VERSION 5.7 ;
  NOWIREEXTENSIONATPIN ON ;
  DIVIDERCHAR "/" ;
  BUSBITCHARS "[]" ;
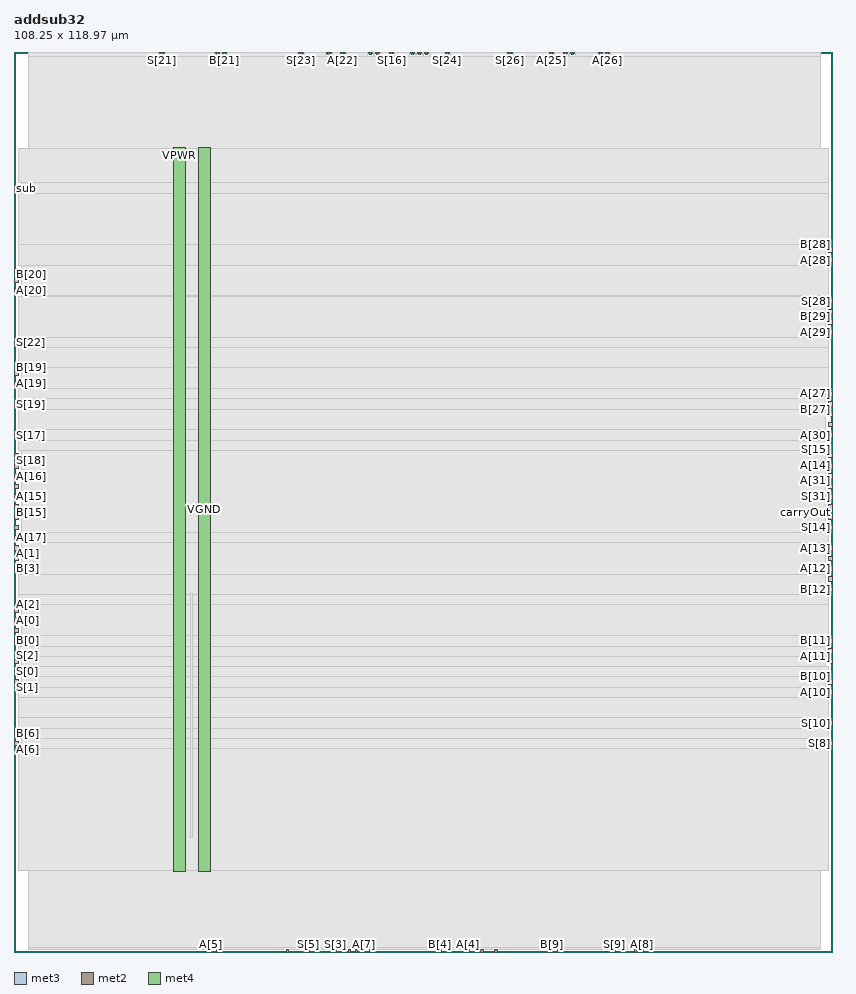
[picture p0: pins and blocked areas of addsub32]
MACRO addsub32
  CLASS BLOCK ;
  FOREIGN addsub32 ;
  ORIGIN 0.000 0.000 ;
  SIZE 108.250 BY 118.970 ;
  PIN A[0]
    DIRECTION INPUT ;
    USE SIGNAL ;
    ANTENNAGATEAREA 0.213000 ;
    PORT
      LAYER met3 ;
        RECT 0.000 43.560 0.600 44.160 ;
    END
  END A[0]
  PIN A[10]
    DIRECTION INPUT ;
    USE SIGNAL ;
    ANTENNAGATEAREA 0.213000 ;
    PORT
      LAYER met3 ;
        RECT 107.650 34.040 108.250 34.640 ;
    END
  END A[10]
  PIN A[11]
    DIRECTION INPUT ;
    USE SIGNAL ;
    ANTENNAGATEAREA 0.213000 ;
    PORT
      LAYER met3 ;
        RECT 107.650 39.480 108.250 40.080 ;
    END
  END A[11]
  PIN A[12]
    DIRECTION INPUT ;
    USE SIGNAL ;
    ANTENNAGATEAREA 0.213000 ;
    PORT
      LAYER met3 ;
        RECT 107.650 50.360 108.250 50.960 ;
    END
  END A[12]
  PIN A[13]
    DIRECTION INPUT ;
    USE SIGNAL ;
    ANTENNAGATEAREA 0.213000 ;
    PORT
      LAYER met3 ;
        RECT 107.650 53.080 108.250 53.680 ;
    END
  END A[13]
  PIN A[14]
    DIRECTION INPUT ;
    USE SIGNAL ;
    ANTENNAGATEAREA 0.213000 ;
    PORT
      LAYER met3 ;
        RECT 107.650 63.960 108.250 64.560 ;
    END
  END A[14]
  PIN A[15]
    DIRECTION INPUT ;
    USE SIGNAL ;
    ANTENNAGATEAREA 0.213000 ;
    PORT
      LAYER met3 ;
        RECT 0.000 59.880 0.600 60.480 ;
    END
  END A[15]
  PIN A[16]
    DIRECTION INPUT ;
    USE SIGNAL ;
    ANTENNAGATEAREA 0.213000 ;
    PORT
      LAYER met3 ;
        RECT 0.000 62.600 0.600 63.200 ;
    END
  END A[16]
  PIN A[17]
    DIRECTION INPUT ;
    USE SIGNAL ;
    ANTENNAGATEAREA 0.213000 ;
    PORT
      LAYER met3 ;
        RECT 0.000 54.440 0.600 55.040 ;
    END
  END A[17]
  PIN A[18]
    DIRECTION INPUT ;
    USE SIGNAL ;
    ANTENNAGATEAREA 0.213000 ;
    PORT
      LAYER met3 ;
        RECT 0.000 65.320 0.600 65.920 ;
    END
  END A[18]
  PIN A[19]
    DIRECTION INPUT ;
    USE SIGNAL ;
    ANTENNAGATEAREA 0.213000 ;
    PORT
      LAYER met3 ;
        RECT 0.000 74.840 0.600 75.440 ;
    END
  END A[19]
  PIN A[1]
    DIRECTION INPUT ;
    USE SIGNAL ;
    ANTENNAGATEAREA 0.213000 ;
    PORT
      LAYER met3 ;
        RECT 0.000 53.080 0.600 53.680 ;
    END
  END A[1]
  PIN A[20]
    DIRECTION INPUT ;
    USE SIGNAL ;
    ANTENNAGATEAREA 0.213000 ;
    PORT
      LAYER met3 ;
        RECT 0.000 87.080 0.600 87.680 ;
    END
  END A[20]
  PIN A[21]
    DIRECTION INPUT ;
    USE SIGNAL ;
    ANTENNAGATEAREA 0.213000 ;
    PORT
      LAYER met2 ;
        RECT 26.770 118.690 27.050 118.970 ;
    END
  END A[21]
  PIN A[22]
    DIRECTION INPUT ;
    USE SIGNAL ;
    ANTENNAGATEAREA 0.213000 ;
    PORT
      LAYER met2 ;
        RECT 43.330 118.690 43.610 118.970 ;
    END
  END A[22]
  PIN A[23]
    DIRECTION INPUT ;
    USE SIGNAL ;
    ANTENNAGATEAREA 0.213000 ;
    PORT
      LAYER met2 ;
        RECT 47.010 118.690 47.290 118.970 ;
    END
  END A[23]
  PIN A[24]
    DIRECTION INPUT ;
    USE SIGNAL ;
    ANTENNAGATEAREA 0.213000 ;
    PORT
      LAYER met2 ;
        RECT 52.530 118.690 52.810 118.970 ;
    END
  END A[24]
  PIN A[25]
    DIRECTION INPUT ;
    USE SIGNAL ;
    ANTENNAGATEAREA 0.213000 ;
    PORT
      LAYER met2 ;
        RECT 70.930 118.690 71.210 118.970 ;
    END
  END A[25]
  PIN A[26]
    DIRECTION INPUT ;
    USE SIGNAL ;
    ANTENNAGATEAREA 0.213000 ;
    PORT
      LAYER met2 ;
        RECT 78.290 118.690 78.570 118.970 ;
    END
  END A[26]
  PIN A[27]
    DIRECTION INPUT ;
    USE SIGNAL ;
    ANTENNAGATEAREA 0.213000 ;
    PORT
      LAYER met3 ;
        RECT 107.650 73.480 108.250 74.080 ;
    END
  END A[27]
  PIN A[28]
    DIRECTION INPUT ;
    USE SIGNAL ;
    ANTENNAGATEAREA 0.213000 ;
    PORT
      LAYER met3 ;
        RECT 107.650 91.160 108.250 91.760 ;
    END
  END A[28]
  PIN A[29]
    DIRECTION INPUT ;
    USE SIGNAL ;
    ANTENNAGATEAREA 0.213000 ;
    PORT
      LAYER met3 ;
        RECT 107.650 81.640 108.250 82.240 ;
    END
  END A[29]
  PIN A[2]
    DIRECTION INPUT ;
    USE SIGNAL ;
    ANTENNAGATEAREA 0.213000 ;
    PORT
      LAYER met3 ;
        RECT 0.000 44.920 0.600 45.520 ;
    END
  END A[2]
  PIN A[30]
    DIRECTION INPUT ;
    USE SIGNAL ;
    ANTENNAGATEAREA 0.213000 ;
    PORT
      LAYER met3 ;
        RECT 107.650 68.040 108.250 68.640 ;
    END
  END A[30]
  PIN A[31]
    DIRECTION INPUT ;
    USE SIGNAL ;
    ANTENNAGATEAREA 0.213000 ;
    PORT
      LAYER met3 ;
        RECT 107.650 61.240 108.250 61.840 ;
    END
  END A[31]
  PIN A[3]
    DIRECTION INPUT ;
    USE SIGNAL ;
    ANTENNAGATEAREA 0.213000 ;
    PORT
      LAYER met2 ;
        RECT 44.250 0.000 44.530 0.280 ;
    END
  END A[3]
  PIN A[4]
    DIRECTION INPUT ;
    USE SIGNAL ;
    ANTENNAGATEAREA 0.213000 ;
    PORT
      LAYER met2 ;
        RECT 59.890 0.000 60.170 0.280 ;
    END
  END A[4]
  PIN A[5]
    DIRECTION INPUT ;
    USE SIGNAL ;
    ANTENNAGATEAREA 0.213000 ;
    PORT
      LAYER met2 ;
        RECT 25.850 0.000 26.130 0.280 ;
    END
  END A[5]
  PIN A[6]
    DIRECTION INPUT ;
    USE SIGNAL ;
    ANTENNAGATEAREA 0.213000 ;
    PORT
      LAYER met3 ;
        RECT 0.000 27.240 0.600 27.840 ;
    END
  END A[6]
  PIN A[7]
    DIRECTION INPUT ;
    USE SIGNAL ;
    ANTENNAGATEAREA 0.213000 ;
    PORT
      LAYER met2 ;
        RECT 46.090 0.000 46.370 0.280 ;
    END
  END A[7]
  PIN A[8]
    DIRECTION INPUT ;
    USE SIGNAL ;
    ANTENNAGATEAREA 0.213000 ;
    PORT
      LAYER met2 ;
        RECT 82.890 0.000 83.170 0.280 ;
    END
  END A[8]
  PIN A[9]
    DIRECTION INPUT ;
    USE SIGNAL ;
    ANTENNAGATEAREA 0.213000 ;
    PORT
      LAYER met2 ;
        RECT 71.850 0.000 72.130 0.280 ;
    END
  END A[9]
  PIN B[0]
    DIRECTION INPUT ;
    USE SIGNAL ;
    ANTENNAGATEAREA 0.126000 ;
    PORT
      LAYER met3 ;
        RECT 0.000 40.840 0.600 41.440 ;
    END
  END B[0]
  PIN B[10]
    DIRECTION INPUT ;
    USE SIGNAL ;
    ANTENNAGATEAREA 0.213000 ;
    PORT
      LAYER met3 ;
        RECT 107.650 35.400 108.250 36.000 ;
    END
  END B[10]
  PIN B[11]
    DIRECTION INPUT ;
    USE SIGNAL ;
    ANTENNAGATEAREA 0.213000 ;
    PORT
      LAYER met3 ;
        RECT 107.650 40.840 108.250 41.440 ;
    END
  END B[11]
  PIN B[12]
    DIRECTION INPUT ;
    USE SIGNAL ;
    ANTENNAGATEAREA 0.213000 ;
    PORT
      LAYER met3 ;
        RECT 107.650 47.640 108.250 48.240 ;
    END
  END B[12]
  PIN B[13]
    DIRECTION INPUT ;
    USE SIGNAL ;
    ANTENNAGATEAREA 0.213000 ;
    PORT
      LAYER met3 ;
        RECT 107.650 51.720 108.250 52.320 ;
    END
  END B[13]
  PIN B[14]
    DIRECTION INPUT ;
    USE SIGNAL ;
    ANTENNAGATEAREA 0.213000 ;
    PORT
      LAYER met3 ;
        RECT 107.650 62.600 108.250 63.200 ;
    END
  END B[14]
  PIN B[15]
    DIRECTION INPUT ;
    USE SIGNAL ;
    ANTENNAGATEAREA 0.213000 ;
    PORT
      LAYER met3 ;
        RECT 0.000 58.520 0.600 59.120 ;
    END
  END B[15]
  PIN B[16]
    DIRECTION INPUT ;
    USE SIGNAL ;
    ANTENNAGATEAREA 0.213000 ;
    PORT
      LAYER met3 ;
        RECT 0.000 57.160 0.600 57.760 ;
    END
  END B[16]
  PIN B[17]
    DIRECTION INPUT ;
    USE SIGNAL ;
    ANTENNAGATEAREA 0.213000 ;
    PORT
      LAYER met3 ;
        RECT 0.000 55.800 0.600 56.400 ;
    END
  END B[17]
  PIN B[18]
    DIRECTION INPUT ;
    USE SIGNAL ;
    ANTENNAGATEAREA 0.213000 ;
    PORT
      LAYER met3 ;
        RECT 0.000 61.240 0.600 61.840 ;
    END
  END B[18]
  PIN B[19]
    DIRECTION INPUT ;
    USE SIGNAL ;
    ANTENNAGATEAREA 0.213000 ;
    PORT
      LAYER met3 ;
        RECT 0.000 76.200 0.600 76.800 ;
    END
  END B[19]
  PIN B[1]
    DIRECTION INPUT ;
    USE SIGNAL ;
    ANTENNAGATEAREA 0.213000 ;
    PORT
      LAYER met3 ;
        RECT 0.000 51.720 0.600 52.320 ;
    END
  END B[1]
  PIN B[20]
    DIRECTION INPUT ;
    USE SIGNAL ;
    ANTENNAGATEAREA 0.213000 ;
    PORT
      LAYER met3 ;
        RECT 0.000 88.440 0.600 89.040 ;
    END
  END B[20]
  PIN B[21]
    DIRECTION INPUT ;
    USE SIGNAL ;
    ANTENNAGATEAREA 0.213000 ;
    PORT
      LAYER met2 ;
        RECT 27.690 118.690 27.970 118.970 ;
    END
  END B[21]
  PIN B[22]
    DIRECTION INPUT ;
    USE SIGNAL ;
    ANTENNAGATEAREA 0.213000 ;
    PORT
      LAYER met2 ;
        RECT 41.490 118.690 41.770 118.970 ;
    END
  END B[22]
  PIN B[23]
    DIRECTION INPUT ;
    USE SIGNAL ;
    ANTENNAGATEAREA 0.213000 ;
    PORT
      LAYER met2 ;
        RECT 47.930 118.690 48.210 118.970 ;
    END
  END B[23]
  PIN B[24]
    DIRECTION INPUT ;
    USE SIGNAL ;
    ANTENNAGATEAREA 0.213000 ;
    PORT
      LAYER met2 ;
        RECT 54.370 118.690 54.650 118.970 ;
    END
  END B[24]
  PIN B[25]
    DIRECTION INPUT ;
    USE SIGNAL ;
    ANTENNAGATEAREA 0.213000 ;
    PORT
      LAYER met2 ;
        RECT 73.690 118.690 73.970 118.970 ;
    END
  END B[25]
  PIN B[26]
    DIRECTION INPUT ;
    USE SIGNAL ;
    ANTENNAGATEAREA 0.213000 ;
    PORT
      LAYER met2 ;
        RECT 77.370 118.690 77.650 118.970 ;
    END
  END B[26]
  PIN B[27]
    DIRECTION INPUT ;
    USE SIGNAL ;
    ANTENNAGATEAREA 0.213000 ;
    PORT
      LAYER met3 ;
        RECT 107.650 72.120 108.250 72.720 ;
    END
  END B[27]
  PIN B[28]
    DIRECTION INPUT ;
    USE SIGNAL ;
    ANTENNAGATEAREA 0.213000 ;
    PORT
      LAYER met3 ;
        RECT 107.650 92.520 108.250 93.120 ;
    END
  END B[28]
  PIN B[29]
    DIRECTION INPUT ;
    USE SIGNAL ;
    ANTENNAGATEAREA 0.213000 ;
    PORT
      LAYER met3 ;
        RECT 107.650 83.000 108.250 83.600 ;
    END
  END B[29]
  PIN B[2]
    DIRECTION INPUT ;
    USE SIGNAL ;
    ANTENNAGATEAREA 0.213000 ;
    PORT
      LAYER met3 ;
        RECT 0.000 42.200 0.600 42.800 ;
    END
  END B[2]
  PIN B[30]
    DIRECTION INPUT ;
    USE SIGNAL ;
    ANTENNAGATEAREA 0.213000 ;
    PORT
      LAYER met3 ;
        RECT 107.650 69.400 108.250 70.000 ;
    END
  END B[30]
  PIN B[31]
    DIRECTION INPUT ;
    USE SIGNAL ;
    ANTENNAGATEAREA 0.213000 ;
    PORT
      LAYER met3 ;
        RECT 107.650 57.160 108.250 57.760 ;
    END
  END B[31]
  PIN B[3]
    DIRECTION INPUT ;
    USE SIGNAL ;
    ANTENNAGATEAREA 0.213000 ;
    PORT
      LAYER met3 ;
        RECT 0.000 50.360 0.600 50.960 ;
    END
  END B[3]
  PIN B[4]
    DIRECTION INPUT ;
    USE SIGNAL ;
    ANTENNAGATEAREA 0.213000 ;
    PORT
      LAYER met2 ;
        RECT 56.210 0.000 56.490 0.280 ;
    END
  END B[4]
  PIN B[5]
    DIRECTION INPUT ;
    USE SIGNAL ;
    ANTENNAGATEAREA 0.213000 ;
    PORT
      LAYER met2 ;
        RECT 26.770 0.000 27.050 0.280 ;
    END
  END B[5]
  PIN B[6]
    DIRECTION INPUT ;
    USE SIGNAL ;
    ANTENNAGATEAREA 0.213000 ;
    PORT
      LAYER met3 ;
        RECT 0.000 28.600 0.600 29.200 ;
    END
  END B[6]
  PIN B[7]
    DIRECTION INPUT ;
    USE SIGNAL ;
    ANTENNAGATEAREA 0.213000 ;
    PORT
      LAYER met2 ;
        RECT 47.010 0.000 47.290 0.280 ;
    END
  END B[7]
  PIN B[8]
    DIRECTION INPUT ;
    USE SIGNAL ;
    ANTENNAGATEAREA 0.213000 ;
    PORT
      LAYER met2 ;
        RECT 81.970 0.000 82.250 0.280 ;
    END
  END B[8]
  PIN B[9]
    DIRECTION INPUT ;
    USE SIGNAL ;
    ANTENNAGATEAREA 0.213000 ;
    PORT
      LAYER met2 ;
        RECT 70.930 0.000 71.210 0.280 ;
    END
  END B[9]
  PIN S[0]
    DIRECTION OUTPUT ;
    USE SIGNAL ;
    ANTENNADIFFAREA 0.702900 ;
    PORT
      LAYER met3 ;
        RECT 0.000 36.760 0.600 37.360 ;
    END
  END S[0]
  PIN S[10]
    DIRECTION OUTPUT ;
    USE SIGNAL ;
    ANTENNADIFFAREA 0.383400 ;
    PORT
      LAYER met3 ;
        RECT 107.650 29.960 108.250 30.560 ;
    END
  END S[10]
  PIN S[11]
    DIRECTION OUTPUT ;
    USE SIGNAL ;
    ANTENNADIFFAREA 0.891000 ;
    PORT
      LAYER met3 ;
        RECT 107.650 38.120 108.250 38.720 ;
    END
  END S[11]
  PIN S[12]
    DIRECTION OUTPUT ;
    USE SIGNAL ;
    ANTENNAGATEAREA 0.126000 ;
    ANTENNADIFFAREA 0.429000 ;
    PORT
      LAYER met2 ;
        RECT 63.570 0.000 63.850 0.280 ;
    END
  END S[12]
  PIN S[13]
    DIRECTION OUTPUT ;
    USE SIGNAL ;
    ANTENNADIFFAREA 0.429000 ;
    PORT
      LAYER met3 ;
        RECT 107.650 49.000 108.250 49.600 ;
    END
  END S[13]
  PIN S[14]
    DIRECTION OUTPUT ;
    USE SIGNAL ;
    ANTENNADIFFAREA 1.336500 ;
    PORT
      LAYER met3 ;
        RECT 107.650 55.800 108.250 56.400 ;
    END
  END S[14]
  PIN S[15]
    DIRECTION OUTPUT ;
    USE SIGNAL ;
    ANTENNADIFFAREA 0.795200 ;
    PORT
      LAYER met3 ;
        RECT 107.650 65.320 108.250 65.920 ;
    END
  END S[15]
  PIN S[16]
    DIRECTION OUTPUT ;
    USE SIGNAL ;
    ANTENNADIFFAREA 1.336500 ;
    PORT
      LAYER met2 ;
        RECT 49.770 118.690 50.050 118.970 ;
    END
  END S[16]
  PIN S[17]
    DIRECTION OUTPUT ;
    USE SIGNAL ;
    ANTENNADIFFAREA 1.336500 ;
    PORT
      LAYER met3 ;
        RECT 0.000 68.040 0.600 68.640 ;
    END
  END S[17]
  PIN S[18]
    DIRECTION OUTPUT ;
    USE SIGNAL ;
    ANTENNADIFFAREA 1.336500 ;
    PORT
      LAYER met3 ;
        RECT 0.000 63.960 0.600 64.560 ;
    END
  END S[18]
  PIN S[19]
    DIRECTION OUTPUT ;
    USE SIGNAL ;
    ANTENNADIFFAREA 1.336500 ;
    PORT
      LAYER met3 ;
        RECT 0.000 72.120 0.600 72.720 ;
    END
  END S[19]
  PIN S[1]
    DIRECTION OUTPUT ;
    USE SIGNAL ;
    ANTENNADIFFAREA 1.336500 ;
    PORT
      LAYER met3 ;
        RECT 0.000 35.400 0.600 36.000 ;
    END
  END S[1]
  PIN S[20]
    DIRECTION OUTPUT ;
    USE SIGNAL ;
    ANTENNADIFFAREA 1.782000 ;
    PORT
      LAYER met3 ;
        RECT 0.000 89.800 0.600 90.400 ;
    END
  END S[20]
  PIN S[21]
    DIRECTION OUTPUT ;
    USE SIGNAL ;
    ANTENNADIFFAREA 1.782000 ;
    PORT
      LAYER met2 ;
        RECT 19.410 118.690 19.690 118.970 ;
    END
  END S[21]
  PIN S[22]
    DIRECTION OUTPUT ;
    USE SIGNAL ;
    ANTENNADIFFAREA 1.336500 ;
    PORT
      LAYER met3 ;
        RECT 0.000 80.280 0.600 80.880 ;
    END
  END S[22]
  PIN S[23]
    DIRECTION OUTPUT ;
    USE SIGNAL ;
    ANTENNADIFFAREA 1.336500 ;
    PORT
      LAYER met2 ;
        RECT 37.810 118.690 38.090 118.970 ;
    END
  END S[23]
  PIN S[24]
    DIRECTION OUTPUT ;
    USE SIGNAL ;
    ANTENNADIFFAREA 1.336500 ;
    PORT
      LAYER met2 ;
        RECT 57.130 118.690 57.410 118.970 ;
    END
  END S[24]
  PIN S[25]
    DIRECTION OUTPUT ;
    USE SIGNAL ;
    ANTENNADIFFAREA 1.336500 ;
    PORT
      LAYER met2 ;
        RECT 53.450 118.690 53.730 118.970 ;
    END
  END S[25]
  PIN S[26]
    DIRECTION OUTPUT ;
    USE SIGNAL ;
    ANTENNADIFFAREA 1.336500 ;
    PORT
      LAYER met2 ;
        RECT 65.410 118.690 65.690 118.970 ;
    END
  END S[26]
  PIN S[27]
    DIRECTION OUTPUT ;
    USE SIGNAL ;
    ANTENNADIFFAREA 1.336500 ;
    PORT
      LAYER met2 ;
        RECT 72.770 118.690 73.050 118.970 ;
    END
  END S[27]
  PIN S[28]
    DIRECTION OUTPUT ;
    USE SIGNAL ;
    ANTENNADIFFAREA 0.383400 ;
    PORT
      LAYER met3 ;
        RECT 107.650 85.720 108.250 86.320 ;
    END
  END S[28]
  PIN S[29]
    DIRECTION OUTPUT ;
    USE SIGNAL ;
    ANTENNADIFFAREA 0.795200 ;
    PORT
      LAYER met3 ;
        RECT 107.650 84.360 108.250 84.960 ;
    END
  END S[29]
  PIN S[2]
    DIRECTION OUTPUT ;
    USE SIGNAL ;
    ANTENNADIFFAREA 1.336500 ;
    PORT
      LAYER met3 ;
        RECT 0.000 38.120 0.600 38.720 ;
    END
  END S[2]
  PIN S[30]
    DIRECTION OUTPUT ;
    USE SIGNAL ;
    ANTENNADIFFAREA 1.336500 ;
    PORT
      LAYER met3 ;
        RECT 107.650 70.760 108.250 71.360 ;
    END
  END S[30]
  PIN S[31]
    DIRECTION OUTPUT ;
    USE SIGNAL ;
    ANTENNADIFFAREA 1.336500 ;
    PORT
      LAYER met3 ;
        RECT 107.650 59.880 108.250 60.480 ;
    END
  END S[31]
  PIN S[3]
    DIRECTION OUTPUT ;
    USE SIGNAL ;
    ANTENNADIFFAREA 1.336500 ;
    PORT
      LAYER met2 ;
        RECT 42.410 0.000 42.690 0.280 ;
    END
  END S[3]
  PIN S[4]
    DIRECTION OUTPUT ;
    USE SIGNAL ;
    ANTENNADIFFAREA 1.336500 ;
    PORT
      LAYER met2 ;
        RECT 61.730 0.000 62.010 0.280 ;
    END
  END S[4]
  PIN S[5]
    DIRECTION OUTPUT ;
    USE SIGNAL ;
    ANTENNADIFFAREA 1.336500 ;
    PORT
      LAYER met2 ;
        RECT 38.730 0.000 39.010 0.280 ;
    END
  END S[5]
  PIN S[6]
    DIRECTION OUTPUT ;
    USE SIGNAL ;
    ANTENNADIFFAREA 1.336500 ;
    PORT
      LAYER met2 ;
        RECT 35.970 0.000 36.250 0.280 ;
    END
  END S[6]
  PIN S[7]
    DIRECTION OUTPUT ;
    USE SIGNAL ;
    ANTENNADIFFAREA 1.336500 ;
    PORT
      LAYER met2 ;
        RECT 45.170 0.000 45.450 0.280 ;
    END
  END S[7]
  PIN S[8]
    DIRECTION OUTPUT ;
    USE SIGNAL ;
    ANTENNADIFFAREA 1.336500 ;
    PORT
      LAYER met3 ;
        RECT 107.650 27.240 108.250 27.840 ;
    END
  END S[8]
  PIN S[9]
    DIRECTION OUTPUT ;
    USE SIGNAL ;
    ANTENNADIFFAREA 0.891000 ;
    PORT
      LAYER met2 ;
        RECT 79.210 0.000 79.490 0.280 ;
    END
  END S[9]
  PIN VGND
    DIRECTION INOUT ;
    USE GROUND ;
    PORT
      LAYER met4 ;
        RECT 24.340 10.640 25.940 106.320 ;
    END
  END VGND
  PIN VPWR
    DIRECTION INOUT ;
    USE POWER ;
    PORT
      LAYER met4 ;
        RECT 21.040 10.640 22.640 106.320 ;
    END
  END VPWR
  PIN carryOut
    DIRECTION OUTPUT ;
    USE SIGNAL ;
    ANTENNADIFFAREA 0.445500 ;
    PORT
      LAYER met3 ;
        RECT 107.650 58.520 108.250 59.120 ;
    END
  END carryOut
  PIN sub
    DIRECTION INPUT ;
    USE SIGNAL ;
    ANTENNAGATEAREA 0.742500 ;
    PORT
      LAYER met3 ;
        RECT 0.000 100.680 0.600 101.280 ;
    END
  END sub
  OBS
      LAYER nwell ;
        RECT 5.330 10.795 102.770 106.270 ;
      LAYER li1 ;
        RECT 5.520 10.795 102.580 106.165 ;
      LAYER met1 ;
        RECT 1.910 10.640 106.650 106.320 ;
      LAYER met2 ;
        RECT 1.930 118.410 19.130 118.900 ;
        RECT 19.970 118.410 26.490 118.900 ;
        RECT 27.330 118.410 27.410 118.900 ;
        RECT 28.250 118.410 37.530 118.900 ;
        RECT 38.370 118.410 41.210 118.900 ;
        RECT 42.050 118.410 43.050 118.900 ;
        RECT 43.890 118.410 46.730 118.900 ;
        RECT 47.570 118.410 47.650 118.900 ;
        RECT 48.490 118.410 49.490 118.900 ;
        RECT 50.330 118.410 52.250 118.900 ;
        RECT 53.090 118.410 53.170 118.900 ;
        RECT 54.010 118.410 54.090 118.900 ;
        RECT 54.930 118.410 56.850 118.900 ;
        RECT 57.690 118.410 65.130 118.900 ;
        RECT 65.970 118.410 70.650 118.900 ;
        RECT 71.490 118.410 72.490 118.900 ;
        RECT 73.330 118.410 73.410 118.900 ;
        RECT 74.250 118.410 77.090 118.900 ;
        RECT 77.930 118.410 78.010 118.900 ;
        RECT 78.850 118.410 106.630 118.900 ;
        RECT 1.930 0.560 106.630 118.410 ;
        RECT 1.930 0.280 25.570 0.560 ;
        RECT 26.410 0.280 26.490 0.560 ;
        RECT 27.330 0.280 35.690 0.560 ;
        RECT 36.530 0.280 38.450 0.560 ;
        RECT 39.290 0.280 42.130 0.560 ;
        RECT 42.970 0.280 43.970 0.560 ;
        RECT 44.810 0.280 44.890 0.560 ;
        RECT 45.730 0.280 45.810 0.560 ;
        RECT 46.650 0.280 46.730 0.560 ;
        RECT 47.570 0.280 55.930 0.560 ;
        RECT 56.770 0.280 59.610 0.560 ;
        RECT 60.450 0.280 61.450 0.560 ;
        RECT 62.290 0.280 63.290 0.560 ;
        RECT 64.130 0.280 70.650 0.560 ;
        RECT 71.490 0.280 71.570 0.560 ;
        RECT 72.410 0.280 78.930 0.560 ;
        RECT 79.770 0.280 81.690 0.560 ;
        RECT 82.530 0.280 82.610 0.560 ;
        RECT 83.450 0.280 106.630 0.560 ;
      LAYER met3 ;
        RECT 0.600 101.680 107.650 106.245 ;
        RECT 1.000 100.280 107.650 101.680 ;
        RECT 0.600 93.520 107.650 100.280 ;
        RECT 0.600 90.800 107.250 93.520 ;
        RECT 1.000 90.760 107.250 90.800 ;
        RECT 1.000 86.720 107.650 90.760 ;
        RECT 1.000 86.680 107.250 86.720 ;
        RECT 0.600 81.280 107.250 86.680 ;
        RECT 1.000 81.240 107.250 81.280 ;
        RECT 1.000 79.880 107.650 81.240 ;
        RECT 0.600 77.200 107.650 79.880 ;
        RECT 1.000 74.480 107.650 77.200 ;
        RECT 1.000 74.440 107.250 74.480 ;
        RECT 0.600 73.120 107.250 74.440 ;
        RECT 1.000 71.720 107.250 73.120 ;
        RECT 0.600 69.040 107.250 71.720 ;
        RECT 1.000 67.640 107.250 69.040 ;
        RECT 0.600 66.320 107.650 67.640 ;
        RECT 1.000 55.400 107.250 66.320 ;
        RECT 1.000 54.080 107.650 55.400 ;
        RECT 1.000 49.960 107.250 54.080 ;
        RECT 0.600 47.240 107.250 49.960 ;
        RECT 0.600 45.920 107.650 47.240 ;
        RECT 1.000 41.840 107.650 45.920 ;
        RECT 1.000 40.440 107.250 41.840 ;
        RECT 0.600 39.120 107.250 40.440 ;
        RECT 1.000 37.720 107.250 39.120 ;
        RECT 1.000 36.400 107.650 37.720 ;
        RECT 1.000 35.000 107.250 36.400 ;
        RECT 0.600 33.640 107.250 35.000 ;
        RECT 0.600 30.960 107.650 33.640 ;
        RECT 0.600 29.600 107.250 30.960 ;
        RECT 1.000 29.560 107.250 29.600 ;
        RECT 1.000 28.240 107.650 29.560 ;
        RECT 1.000 26.840 107.250 28.240 ;
        RECT 0.600 10.715 107.650 26.840 ;
      LAYER met4 ;
        RECT 23.295 15.135 23.625 47.425 ;
  END
END addsub32
END LIBRARY

